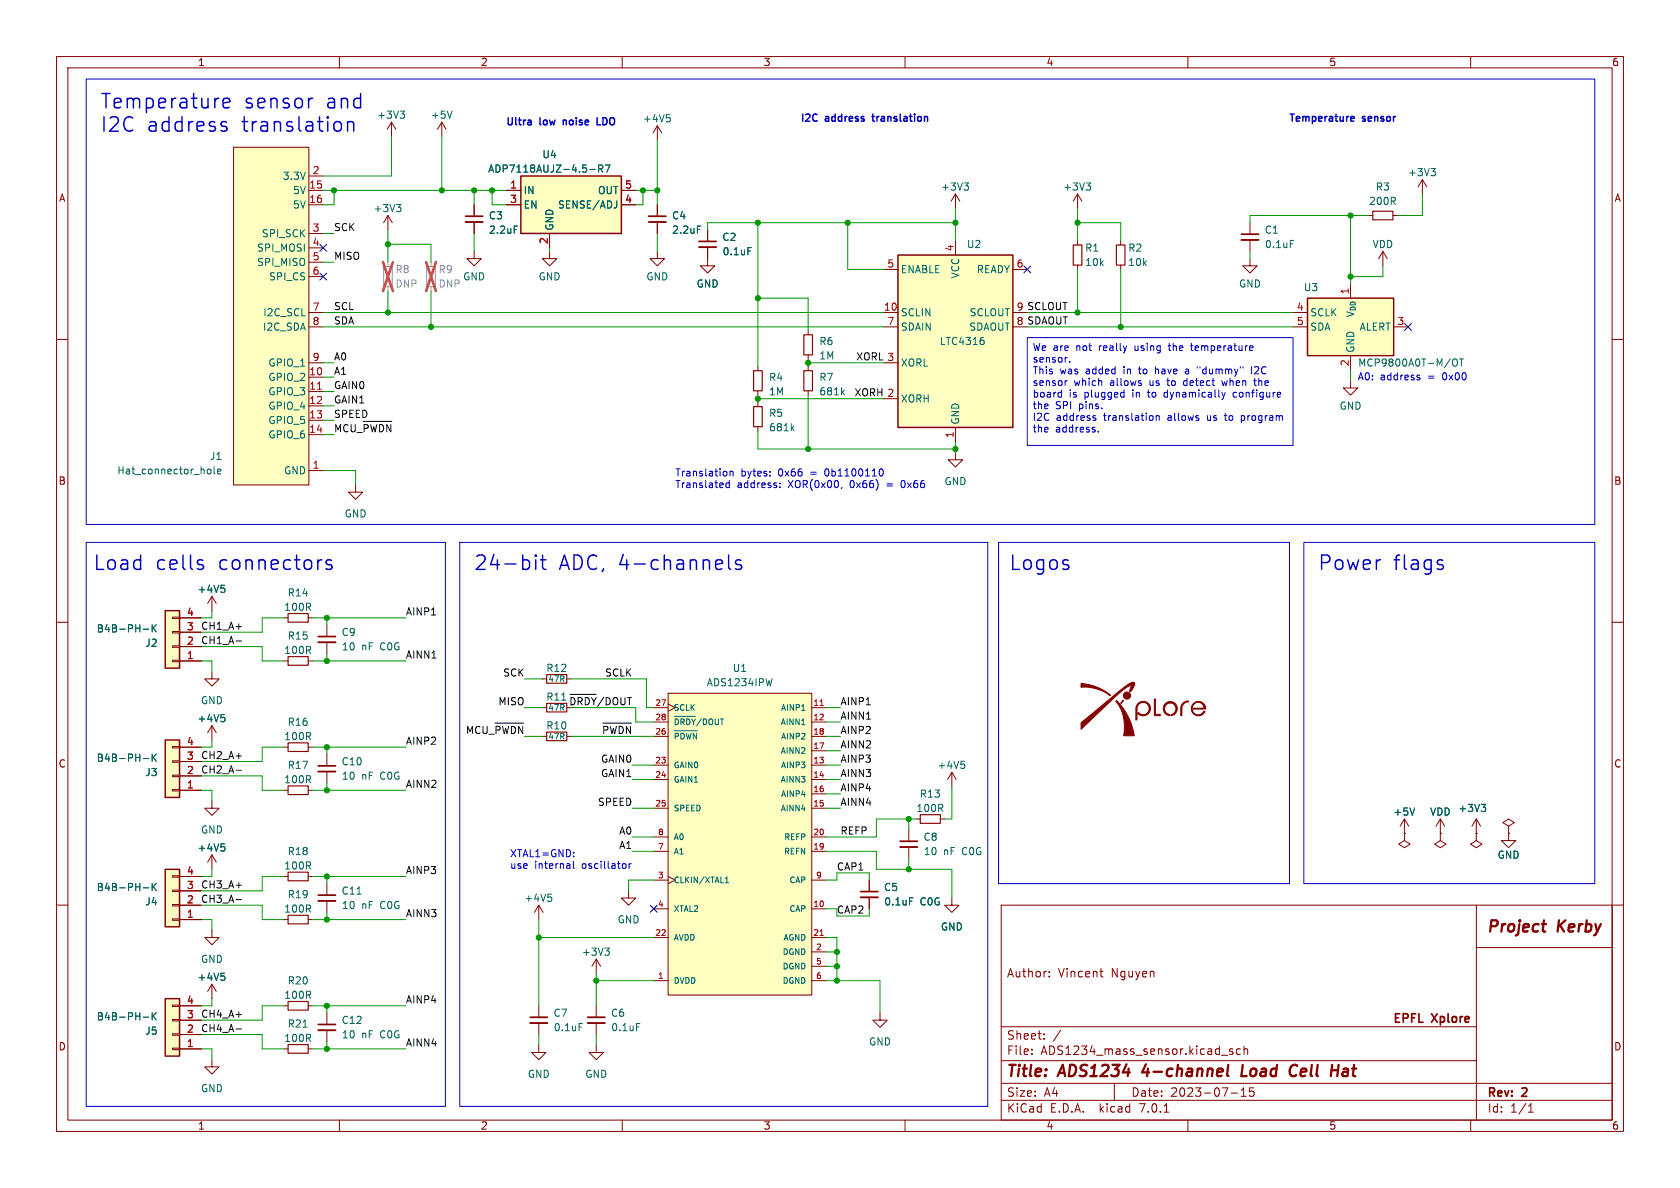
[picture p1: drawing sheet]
<svg xmlns="http://www.w3.org/2000/svg" width="297mm" height="210mm" viewBox="0 0 297 210" stroke-linecap="round" stroke-linejoin="round" font-family="sans-serif">
<defs><g id="words">
<g font-size="3.5" fill="#0000c2">
<text x="17.8" y="19.4">Temperature</text>
<text x="17.8" y="23.5">I2C</text>
<text x="26" y="23.5">address</text>
<text x="42.8" y="23.5">translation</text>
<text x="43.2" y="19.4">sensor</text>
<text x="57.7" y="19.4">and</text>
<text x="16.5" y="101">Load</text>
<text x="27.5" y="101">cells</text>
<text x="38.7" y="101">connectors</text>
<text x="83.8" y="101">24-bit</text>
<text x="98.8" y="101">ADC, 4-channels</text>
<text x="178.4" y="101">Logos</text>
<text x="233" y="101">Power</text>
<text x="246.4" y="101">flags</text>
</g>
<g font-size="2.8" fill="#840000">
<text x="262.7" y="165.3">Project</text>
<text x="275.2" y="165.3">Kerby</text>
<text x="178" y="190.8">Title:</text>
<text x="187.4" y="190.8">ADS1234</text>
<text x="202.7" y="190.8">4-channel</text>
<text x="220.8" y="190.8">Load</text>
<text x="229.9" y="190.8">Cell</text>
<text x="237.8" y="190.8">Hat</text>
</g>
<g font-size="2.1" fill="#840000">
<text x="178" y="172.9">Author:</text>
<text x="187.1" y="172.9">Vincent</text>
<text x="196.4" y="172.9">Nguyen</text>
<text x="178" y="183.9">Sheet:</text>
<text x="186.2" y="183.9">/</text>
<text x="245.9" y="181.1">EPFL</text>
<text x="252.9" y="181.1">Xplore</text>
<text x="178" y="186.6">File:</text>
<text x="184" y="186.6">ADS1234_mass_sensor.kicad_sch</text>
<text x="178" y="196.8">KiCad</text>
<text x="178" y="194">Size:</text>
<text x="184.6" y="194">A4</text>
<text x="185.7" y="196.8">E.D.A.</text>
<text x="194.4" y="196.8">kicad</text>
<text x="200" y="194">Date:</text>
<text x="201.5" y="196.8">7.0.1</text>
<text x="206.9" y="194">2023-07-15</text>
<text x="263" y="194.2">Rev:</text>
<text x="263" y="196.8">Id:</text>
<text x="267" y="196.8">1/1</text>
<text x="269.2" y="194.2">2</text>
</g>
<g font-size="1.8" fill="#840000">
<text x="35" y="11.8">1</text>
<text x="85" y="11.8">2</text>
<text x="135" y="11.8">3</text>
<text x="185" y="11.8">4</text>
<text x="235" y="11.8">5</text>
<text x="285" y="11.8">6</text>
<text x="10.4" y="35.8">A</text>
<text x="285.4" y="35.8">A</text>
<text x="10.3" y="85.8">B</text>
<text x="285.3" y="85.8">B</text>
<text x="10.3" y="135.8">C</text>
<text x="285.3" y="135.8">C</text>
<text x="10.3" y="185.8">D</text>
<text x="285.3" y="185.8">D</text>
<text x="35" y="199.8">1</text>
<text x="85" y="199.8">2</text>
<text x="135" y="199.8">3</text>
<text x="185" y="199.8">4</text>
<text x="235" y="199.8">5</text>
<text x="285" y="199.8">6</text>
</g>
<g font-size="1.8" fill="#006464">
<text x="66.6" y="21.1">+3V3</text>
<text x="76.1" y="21.1">+5V</text>
<text x="113.6" y="21.8">+4V5</text>
<text x="95.8" y="28.1">U4</text>
<text x="49.9" y="31.9">3.3V</text>
<text x="51.7" y="34.5">5V</text>
<text x="86.2" y="30.7">ADP7118AUJZ-4.5-R7</text>
<text x="92.6" y="34.5">IN</text>
<text x="105.6" y="34.5">OUT</text>
<text x="166.3" y="33.8">+3V3</text>
<text x="187.9" y="33.8">+3V3</text>
<text x="243.2" y="33.8">R3</text>
<text x="248.9" y="31.3">+3V3</text>
<text x="51.7" y="37">5V</text>
<text x="66" y="37.7">+3V3</text>
<text x="86.4" y="38.9">C3</text>
<text x="86.4" y="41.5">2.2uF</text>
<text x="92.6" y="37">EN</text>
<text x="98" y="40.8" transform="rotate(-90 98 40.8)">GND</text>
<text x="98.5" y="37">SENSE/ADJ</text>
<text x="118.8" y="38.9">C4</text>
<text x="118.8" y="41.5">2.2uF</text>
<text x="223.5" y="41.5">C1</text>
<text x="242" y="36.4">200R</text>
<text x="45.3" y="44.6">SPI_MOSI</text>
<text x="45.3" y="47.2">SPI_MISO</text>
<text x="46.2" y="42.1">SPI_SCK</text>
<text x="127.6" y="42.7">C2</text>
<text x="127.7" y="45.3">0.1uF</text>
<text x="170.9" y="44">U2</text>
<text x="191.8" y="44.6">R1</text>
<text x="191.8" y="47.2">10k</text>
<text x="199.4" y="44.6">R2</text>
<text x="199.4" y="47.2">10k</text>
<text x="223.6" y="44">0.1uF</text>
<text x="242.6" y="44">VDD</text>
<text x="47.4" y="49.7">SPI_CS</text>
<text x="81.8" y="49.7">GND</text>
<text x="95.2" y="49.7">GND</text>
<text x="114.2" y="49.7">GND</text>
<text x="123.1" y="51">GND</text>
<text x="159.3" y="48.5">ENABLE</text>
<text x="169.7" y="49.3" transform="rotate(-90 169.7 49.3)">VCC</text>
<text x="172.6" y="48.5">READY</text>
<text x="219" y="51">GND</text>
<text x="230.4" y="51.6">U3</text>
<text x="46.4" y="58.6">I2C_SDA</text>
<text x="46.4" y="56.1">I2C_SCL</text>
<text x="159.3" y="56.1">SCLIN</text>
<text x="159.3" y="58.6">SDAIN</text>
<text x="171.2" y="58.6">SDAOUT</text>
<text x="171.3" y="56.1">SCLOUT</text>
<text x="231.6" y="56.1">SCLK</text>
<text x="231.6" y="58.6">SDA</text>
<text x="239.6" y="56.3" transform="rotate(-90 239.6 56.3)">V_{DD}</text>
<text x="240.2" y="58.6">ALERT</text>
<text x="47.3" y="65">GPIO_1</text>
<text x="144.8" y="61.2">R6</text>
<text x="144.8" y="63.7">1M</text>
<text x="159.3" y="65">XORL</text>
<text x="166.1" y="61.2">LTC4316</text>
<text x="239.6" y="62.4" transform="rotate(-90 239.6 62.4)">GND</text>
<text x="240" y="65">MCP9800A0T-M/OT</text>
<text x="47.3" y="67.5">GPIO_2</text>
<text x="47.3" y="70">GPIO_3</text>
<text x="135.9" y="67.5">R4</text>
<text x="135.9" y="70">1M</text>
<text x="144.8" y="67.5">R7</text>
<text x="144.8" y="70">681k</text>
<text x="159.3" y="71.3">XORH</text>
<text x="47.3" y="72.6">GPIO_4</text>
<text x="47.3" y="75.1">GPIO_5</text>
<text x="47.3" y="77.7">GPIO_6</text>
<text x="135.9" y="73.9">R5</text>
<text x="135.9" y="76.4">681k</text>
<text x="169.7" y="75.1" transform="rotate(-90 169.7 75.1)">GND</text>
<text x="236.8" y="72.6">GND</text>
<text x="37.1" y="81.5">J1</text>
<text x="20.7" y="84">Hat_connector_hole</text>
<text x="50.1" y="84">GND</text>
<text x="166.9" y="85.9">GND</text>
<text x="60.9" y="91.6">GND</text>
<text x="34.9" y="105">+4V5</text>
<text x="50.8" y="105.6">R14</text>
<text x="17" y="112">B4B-PH-K</text>
<text x="50.2" y="108.1">100R</text>
<text x="50.8" y="113.2">R15</text>
<text x="60.3" y="112.6">C9</text>
<text x="25.6" y="114.5">J2</text>
<text x="50.2" y="115.8">100R</text>
<text x="60.4" y="115.1">10</text>
<text x="63.9" y="115.1">nF</text>
<text x="67.2" y="115.1">C0G</text>
<text x="96.5" y="118.9">R12</text>
<text x="129.5" y="118.9">U1</text>
<text x="35.5" y="124.7">GND</text>
<text x="96.5" y="124">R11</text>
<text x="124.9" y="121.5">ADS1234IPW</text>
<text x="34.9" y="127.8">+4V5</text>
<text x="50.2" y="131">100R</text>
<text x="50.8" y="128.5">R16</text>
<text x="96.5" y="129.1">R10</text>
<text x="17" y="134.8">B4B-PH-K</text>
<text x="25.6" y="137.4">J3</text>
<text x="50.8" y="136.1">R17</text>
<text x="60.3" y="135.4">C10</text>
<text x="60.4" y="138">10</text>
<text x="63.9" y="138">nF</text>
<text x="67.2" y="138">C0G</text>
<text x="165.7" y="136.1">+4V5</text>
<text x="50.2" y="138.6">100R</text>
<text x="162" y="143.7">100R</text>
<text x="162.6" y="141.2">R13</text>
<text x="257.7" y="143.7">+3V3</text>
<text x="35.5" y="147.5">GND</text>
<text x="163.2" y="148.8">C8</text>
<text x="246.3" y="144.3">+5V</text>
<text x="252.8" y="144.3">VDD</text>
<text x="34.9" y="150.7">+4V5</text>
<text x="50.2" y="153.9">100R</text>
<text x="50.8" y="151.3">R18</text>
<text x="163.2" y="151.3">10</text>
<text x="166.8" y="151.3">nF</text>
<text x="170.1" y="151.3">C0G</text>
<text x="264.7" y="152">GND</text>
<text x="17" y="157.7">B4B-PH-K</text>
<text x="25.6" y="160.2">J4</text>
<text x="50.2" y="161.5">100R</text>
<text x="50.8" y="158.9">R19</text>
<text x="60.3" y="158.3">C11</text>
<text x="60.4" y="160.9">10</text>
<text x="63.9" y="160.9">nF</text>
<text x="67.2" y="160.9">C0G</text>
<text x="92.6" y="159.6">+4V5</text>
<text x="156.2" y="157.7">C5</text>
<text x="156.3" y="160.2">0.1uF</text>
<text x="162.6" y="160.2">C0G</text>
<text x="109.1" y="163.4">GND</text>
<text x="166.3" y="164.7">GND</text>
<text x="34.9" y="173.5">+4V5</text>
<text x="35.5" y="170.4">GND</text>
<text x="102.8" y="169.1">+3V3</text>
<text x="50.2" y="176.7">100R</text>
<text x="50.8" y="174.2">R20</text>
<text x="97.8" y="179.9">C7</text>
<text x="108" y="179.9">C6</text>
<text x="17" y="180.5">B4B-PH-K</text>
<text x="25.6" y="183.1">J5</text>
<text x="50.2" y="184.3">100R</text>
<text x="50.8" y="181.8">R21</text>
<text x="60.3" y="181.2">C12</text>
<text x="60.4" y="183.7">10</text>
<text x="63.9" y="183.7">nF</text>
<text x="67.2" y="183.7">C0G</text>
<text x="97.8" y="182.4">0.1uF</text>
<text x="108" y="182.4">0.1uF</text>
<text x="153.6" y="185">GND</text>
<text x="93.3" y="190.7">GND</text>
<text x="103.4" y="190.7">GND</text>
<text x="35.5" y="193.2">GND</text>
</g>
<g font-size="1.8" fill="#0000c2">
<text x="89.5" y="22.2">Ultra</text>
<text x="95.5" y="22.2">low</text>
<text x="100" y="22.2">noise</text>
<text x="106.4" y="22.2">LDO</text>
<text x="141.6" y="21.6">I2C</text>
<text x="146" y="21.6">address</text>
<text x="154.8" y="21.6">translation</text>
<text x="228" y="21.6">Temperature</text>
<text x="241" y="21.6">sensor</text>
<text x="182.6" y="62.3">We are</text>
<text x="182.6" y="64.4">sensor.</text>
<text x="190.3" y="62.3">not</text>
<text x="194.4" y="62.3">really</text>
<text x="200.9" y="62.3">using</text>
<text x="207" y="62.3">the</text>
<text x="211.1" y="62.3">temperature</text>
<text x="182.6" y="66.4">This</text>
<text x="182.6" y="68.5">sensor</text>
<text x="182.6" y="70.5">board</text>
<text x="187.4" y="66.4">was</text>
<text x="189" y="70.5">is</text>
<text x="189.9" y="68.5">which</text>
<text x="191.8" y="70.5">plugged</text>
<text x="192" y="66.4">added</text>
<text x="196.3" y="68.5">allows</text>
<text x="198.8" y="66.4">in</text>
<text x="200.4" y="70.5">in</text>
<text x="201.6" y="66.4">to</text>
<text x="203.2" y="70.5">to</text>
<text x="203.4" y="68.5">us</text>
<text x="204.6" y="66.4">have</text>
<text x="206.2" y="70.5">dynamically</text>
<text x="206.7" y="68.5">to</text>
<text x="209.6" y="68.5">detect</text>
<text x="210.1" y="66.4">a</text>
<text x="212.3" y="66.4">&quot;dummy&quot;</text>
<text x="216.6" y="68.5">when</text>
<text x="218.5" y="70.5">configure</text>
<text x="222" y="66.4">I2C</text>
<text x="222.4" y="68.5">the</text>
<text x="240" y="67.3">A0:</text>
<text x="244" y="67.3">address</text>
<text x="252.5" y="67.3">=</text>
<text x="255.2" y="67.3">0x00</text>
<text x="182.6" y="72.6">the</text>
<text x="182.6" y="74.6">I2C</text>
<text x="182.6" y="76.7">the</text>
<text x="186.6" y="72.6">SPI</text>
<text x="186.6" y="76.7">address.</text>
<text x="186.7" y="74.6">address</text>
<text x="190.8" y="72.6">pins.</text>
<text x="195.2" y="74.6">translation</text>
<text x="206.6" y="74.6">allows</text>
<text x="213.7" y="74.6">us</text>
<text x="216.9" y="74.6">to</text>
<text x="219.9" y="74.6">program</text>
<text x="119.4" y="84.3">Translation</text>
<text x="119.4" y="86.4">Translated</text>
<text x="130.3" y="86.4">address:</text>
<text x="131" y="84.3">bytes:</text>
<text x="137.7" y="84.3">0x66</text>
<text x="139.4" y="86.4">XOR(0x00,</text>
<text x="143.4" y="84.3">=</text>
<text x="146.1" y="84.3">0b1100110</text>
<text x="150.4" y="86.4">0x66)</text>
<text x="157" y="86.4">=</text>
<text x="159.7" y="86.4">0x66</text>
<text x="90.2" y="151.6">XTAL1=GND:</text>
<text x="90.2" y="153.7">use</text>
<text x="94.5" y="153.7">internal</text>
<text x="102.9" y="153.7">oscillator</text>
</g>
<g font-size="1.8" fill="#a90000">
<text x="54.6" y="33.4">15</text>
<text x="54.6" y="35.9">16</text>
<text x="55.2" y="30.9">2</text>
<text x="90.1" y="33.4">1</text>
<text x="90.1" y="35.9">3</text>
<text x="110.5" y="33.4">5</text>
<text x="110.5" y="35.9">4</text>
<text x="55.2" y="41">3</text>
<text x="55.2" y="43.6">4</text>
<text x="55.2" y="46.1">5</text>
<text x="96.9" y="43.2" transform="rotate(-90 96.9 43.2)">2</text>
<text x="156.8" y="47.4">5</text>
<text x="168.7" y="44.5" transform="rotate(-90 168.7 44.5)">4</text>
<text x="179.7" y="47.4">6</text>
<text x="55.2" y="48.6">6</text>
<text x="238.5" y="52.1" transform="rotate(-90 238.5 52.1)">1</text>
<text x="55.2" y="55">7</text>
<text x="55.2" y="57.5">8</text>
<text x="156.2" y="55">10</text>
<text x="156.8" y="57.5">7</text>
<text x="229.2" y="55">4</text>
<text x="229.2" y="57.5">5</text>
<text x="247" y="57.5">3</text>
<text x="55.2" y="63.9">9</text>
<text x="238.5" y="64.8" transform="rotate(-90 238.5 64.8)">2</text>
<text x="54.6" y="66.4">10</text>
<text x="54.6" y="69">11</text>
<text x="54.6" y="71.5">12</text>
<text x="54.6" y="74">13</text>
<text x="54.6" y="76.6">14</text>
<text x="168.7" y="77.5" transform="rotate(-90 168.7 77.5)">1</text>
<text x="55.2" y="82.9">1</text>
<text x="33" y="111.5">3</text>
<text x="33" y="109">4</text>
<text x="33" y="116.6">1</text>
<text x="33" y="114">2</text>
<text x="33" y="131.8">4</text>
<text x="33" y="136.9">2</text>
<text x="33" y="134.4">3</text>
<text x="33" y="139.4">1</text>
<text x="33" y="154.7">4</text>
<text x="33" y="159.8">2</text>
<text x="33" y="157.2">3</text>
<text x="33" y="162.3">1</text>
<text x="33" y="177.5">4</text>
<text x="33" y="185.2">1</text>
<text x="33" y="182.6">2</text>
<text x="33" y="180.1">3</text>
</g>
<g font-size="1.8" fill="#0f0f0f">
<text x="59.1" y="40.9">SCK</text>
<text x="59.1" y="46">MISO</text>
<text x="59.1" y="54.9">SCL</text>
<text x="59.1" y="57.4">SDA</text>
<text x="179.7" y="57.5">8 SDAOUT</text>
<text x="179.7" y="55">9 SCLOUT</text>
<text x="59.1" y="63.8">A0</text>
<text x="151.2" y="63.8">XORL 3</text>
<text x="59.1" y="68.9">GAIN0</text>
<text x="59.1" y="71.4">GAIN1</text>
<text x="59.1" y="66.3">A1</text>
<text x="150.9" y="70.1">XORH 2</text>
<text x="59.1" y="76.5">MCU_~{PWDN}</text>
<text x="59.1" y="73.9">SPEED</text>
<text x="35.6" y="114">CH1_A-</text>
<text x="35.6" y="111.4">CH1_A+</text>
<text x="71.8" y="108.9">AINP1</text>
<text x="71.8" y="116.5">AINN1</text>
<text x="88.8" y="119.7">SCK</text>
<text x="106.9" y="119.7">SCLK</text>
<text x="88" y="124.7">MISO</text>
<text x="100.5" y="124.7">~{DRDY}/DOUT</text>
<text x="148.6" y="124.7">AINP1</text>
<text x="71.8" y="131.7">AINP2</text>
<text x="82.2" y="129.8">MCU_~{PWDN}</text>
<text x="106.3" y="129.8">~{PWDN}</text>
<text x="148.6" y="127.3">AINN1</text>
<text x="148.6" y="129.8">AINP2</text>
<text x="35.6" y="136.8">CH2_A-</text>
<text x="35.6" y="134.3">CH2_A+</text>
<text x="106.1" y="134.9">GAIN0</text>
<text x="106.1" y="137.4">GAIN1</text>
<text x="148.6" y="134.9">AINP3</text>
<text x="148.6" y="137.4">AINN3</text>
<text x="148.6" y="132.4">AINN2</text>
<text x="71.8" y="139.4">AINN2</text>
<text x="105.6" y="142.5">SPEED</text>
<text x="148.6" y="140">AINP4</text>
<text x="148.6" y="142.5">AINN4</text>
<text x="109.3" y="147.6">A0</text>
<text x="148.6" y="147.6">REFP</text>
<text x="71.8" y="154.6">AINP3</text>
<text x="109.3" y="150.1">A1</text>
<text x="148" y="154">CAP1</text>
<text x="35.6" y="159.7">CH3_A-</text>
<text x="35.6" y="157.1">CH3_A+</text>
<text x="71.8" y="162.2">AINN3</text>
<text x="35.6" y="180">CH4_A+</text>
<text x="71.8" y="177.5">AINP4</text>
<text x="35.6" y="182.5">CH4_A-</text>
<text x="71.8" y="185.1">AINN4</text>
</g>
<g font-size="1.8" fill="#989898">
<text x="69.9" y="48.5">R8</text>
<text x="69.9" y="51">DNP</text>
<text x="77.5" y="48.5">R9</text>
<text x="77.5" y="51">DNP</text>
</g>
<text font-size="1.8" fill="#009600" x="148" y="161.6">CAP2</text>
<g font-size="1.4" fill="#006464">
<text x="96.9" y="125.8">47R</text>
<text x="96.9" y="120.7">47R</text>
<text x="119.1" y="125.8">SCLK</text>
<text x="137.9" y="125.8">AINP1</text>
<text x="96.9" y="130.9">47R</text>
<text x="119.1" y="131.4">~{PDWN}</text>
<text x="119.1" y="128.8">~{DRDY}/DOUT</text>
<text x="137.9" y="128.3">AINN1</text>
<text x="137.9" y="130.9">AINP2</text>
<text x="119.1" y="136">GAIN0</text>
<text x="137.9" y="133.4">AINN2</text>
<text x="137.9" y="136">AINP3</text>
<text x="119.1" y="138.5">GAIN1</text>
<text x="119.1" y="143.6">SPEED</text>
<text x="137.9" y="138.5">AINN3</text>
<text x="137.9" y="143.6">AINN4</text>
<text x="137.9" y="141">AINP4</text>
<text x="119.1" y="148.7">A0</text>
<text x="138.5" y="148.7">REFP</text>
<text x="119.1" y="151.2">A1</text>
<text x="138.4" y="151.2">REFN</text>
<text x="119.1" y="156.3">CLKIN/XTAL1</text>
<text x="119.1" y="161.4">XTAL2</text>
<text x="139.4" y="161.4">CAP</text>
<text x="139.4" y="156.3">CAP</text>
<text x="119.1" y="166.4">AVDD</text>
<text x="138.3" y="166.4">AGND</text>
<text x="138.2" y="169">DGND</text>
<text x="138.2" y="171.5">DGND</text>
<text x="119.1" y="174.1">DVDD</text>
<text x="138.2" y="174.1">DGND</text>
</g>
<g font-size="1.4" fill="#a90000">
<text x="115.8" y="124.8">27</text>
<text x="143.7" y="124.8">11</text>
<text x="115.8" y="129.9">26</text>
<text x="115.8" y="127.4">28</text>
<text x="143.7" y="127.4">12</text>
<text x="143.7" y="129.9">18</text>
<text x="115.8" y="135">23</text>
<text x="115.8" y="137.5">24</text>
<text x="143.7" y="135">13</text>
<text x="143.7" y="137.5">14</text>
<text x="143.7" y="132.5">17</text>
<text x="115.8" y="142.6">25</text>
<text x="143.7" y="142.6">15</text>
<text x="143.7" y="140.1">16</text>
<text x="116.3" y="147.7">8</text>
<text x="143.7" y="147.7">20</text>
<text x="116.3" y="155.3">3</text>
<text x="116.3" y="150.2">7</text>
<text x="143.7" y="150.2">19</text>
<text x="144.2" y="155.3">9</text>
<text x="116.3" y="160.4">4</text>
<text x="143.7" y="160.4">10</text>
<text x="115.8" y="165.5">22</text>
<text x="143.7" y="165.5">21</text>
<text x="116.3" y="173.1">1</text>
<text x="144.2" y="168">2</text>
<text x="144.2" y="170.6">5</text>
<text x="144.2" y="173.1">6</text>
</g>
</g></defs>
<g fill="none" stroke="#840000" stroke-width=".18">
<path d="M10 10h277v190h-277zM12 12h273v186h-273zM60 10v2M110 10v2M160 10v2M210 10v2M260 10v2M41.3 26h13.3v59.7h-13.3zM54.6 33.7h2.5M54.6 36.2h2.5M54.6 31.1h2.5M68.6 38.1l-.8 1.3"/>
<path d="M68.6 38.1v2.5M68.6 38.1l.7 1.3M69.2 21.6l-.7 1.3M69.2 21.6v2.5M69.2 21.6l.8 1.3M78.1 21.6l-.8 1.3M78.1 21.6v2.5M78.1 21.6l.8 1.3M83.8 36.2v2M83.8 39.2v2.1M89.5 33.7h2.6M89.5 36.2h2.6"/>
<path d="M109.9 33.7h2.5M109.9 36.2h2.5M116.2 22.2v2.6M116.2 36.2v2M116.2 39.2v2.1M116.2 22.2l-.8 1.3M116.2 22.2l.8 1.3M168.9 34.3v2.5M168.9 34.3l.8 1.3M168.9 34.3l-.8 1.3M190.5 34.3l-.8 1.3M190.5 34.3v2.5"/>
<path d="M190.5 34.3l.8 1.3M221 39.4v2M241.9 38.1h.8M246.3 38.1h.7M251.5 31.8l-.8 1.2M251.5 31.8v2.5M251.5 31.8l.7 1.2M10 60h2M54.6 57.8h2.5M54.6 55.2h2.5M54.6 41.3h2.5M54.6 43.8h2.5"/>
<path d="M54.6 46.4h2.5M54.6 48.9h2.5M83.8 44.5v1.2h-1.3l1.3 1.3 1.3-1.3h-1.3M97.2 44.5v1.2h-1.3l1.3 1.3 1.2-1.3h-1.2M97.2 41.3v2.5M116.2 44.5v1.2h-1.3l1.3 1.3 1.3-1.3h-1.3M125.1 43.7v3.3h-1.3l1.3 1.3 1.3-1.3h-1.3M125.1 40.6v2.1M142.9 58.4v.8M156.2 57.8h2.5M156.2 55.2h2.5M156.2 47.6h2.5"/>
<path d="M168.9 42.5v2.6M179.1 57.8h2.5M179.1 55.2h2.5M179.1 47.6h2.5M190.5 42.5v.8M190.5 46.9v.7M198.1 42.5v.8M198.1 46.9v.7M221 45.7v1.3h-1.3l1.3 1.3 1.2-1.3h-1.2M221 42.4v2.1M228.6 57.8h2.5M228.6 55.2h2.5"/>
<path d="M244.5 44.5l-.8 1.2M244.5 44.5v2.5M244.5 44.5l.7 1.2M246.4 57.8h2.5M285 60h2M54.6 66.7h2.5M54.6 69.2h2.5M54.6 71.8h2.5M54.6 74.3h2.5M54.6 76.8h2.5M54.6 64.1h2.5M134 64.8v.7"/>
<path d="M134 69.1v.8M134 71.1v.8M134 75.4v.8M142.9 62.7v.8M142.9 64.8v.7M142.9 69.1v.8M156.2 64.1h2.5M156.2 70.5h2.5M168.9 75.6v2.5M238.8 67.3v1.3h1.2l-1.2 1.3-1.3-1.3h1.3M238.8 62.9v2.5M54.6 83.2h2.5"/>
<path d="M62.9 85.7v1.3h1.2l-1.2 1.3-1.3-1.3h1.3M168.9 80v1.3h1.3l-1.3 1.3-1.3-1.3h1.3M10 110h2M30.5 109.1h1.2v.2h-1.2zM30.5 111.6h1.2v.3h-1.2zM30.5 114.2h1.2v.2h-1.2zM30.5 116.7h1.2v.3h-1.2zM31.7 116.8h3.9M31.7 114.3h3.9M31.7 111.8h3.9M31.7 109.2h3.9M37.5 118.7v1.3h-1.3l1.3 1.3 1.2-1.3h-1.2"/>
<path d="M37.5 105.4v2.6M37.5 105.4l-.8 1.3M37.5 105.4l.7 1.3M50.2 116.8h.7M50.2 109.2h.7M54.5 116.8h.7M54.5 109.2h.7M57.8 110.5v2M57.8 113.5v2.1M285 110h2M30.5 132h1.2v.2h-1.2zM30.5 134.5h1.2v.2h-1.2z"/>
<path d="M30.5 137h1.2v.3h-1.2zM30.5 139.6h1.2v.2h-1.2zM31.7 132.1h3.9M31.7 139.7h3.9M31.7 137.2h3.9M31.7 134.6h3.9M37.5 128.3v2.5M37.5 128.3l-.8 1.2M37.5 128.3l.7 1.2M50.2 132.1h.7M50.2 139.7h.7M54.5 132.1h.7"/>
<path d="M54.5 139.7h.7M57.8 133.4v2M57.8 136.4v2M95.9 130.2h.7M95.9 125.1h.7M95.9 120h.7M100.2 130.2h.8M100.2 120h.8M115.6 130.2h2.5M115.6 125.1h2.5M115.6 127.6h2.5M115.6 135.3h2.5"/>
<path d="M115.6 137.8h2.5M118.1 122.6h25.4v53.3h-25.4zM118.1 124.5l1.3 .6-1.3 .6M143.5 130.2h2.5M143.5 125.1h2.5M143.5 127.6h2.5M143.5 135.3h2.5M143.5 137.8h2.5M143.5 132.7h2.5M168.3 136.5v2.6M168.3 136.5l-.8 1.3M168.3 136.5l.7 1.3"/>
<path d="M10 160h2M30.5 154.8h1.2v.3h-1.2zM30.5 157.4h1.2v.2h-1.2zM30.5 159.9h1.2v.2h-1.2zM31.7 157.5h3.9M31.7 154.9h3.9M37.5 141.6v1.3h-1.3l1.3 1.2 1.2-1.2h-1.2M37.5 151.1v2.6M37.5 151.1l-.8 1.3M37.5 151.1l.7 1.3M50.2 154.9h.7M54.5 154.9h.7"/>
<path d="M57.8 156.2v2M57.8 159.3v2M111.1 157.5v1.3h1.3l-1.3 1.2-1.2-1.2h1.2M115.6 142.9h2.5M115.6 150.5h2.5M115.6 148h2.5M115.6 155.6h2.5M118.1 154.9l1.3 .7-1.3 .6M143.5 142.9h2.5M143.5 140.3h2.5M143.5 150.5h2.5M143.5 148h2.5"/>
<path d="M143.5 155.6h2.5M153.7 155.6v2M153.7 158.6v2.1M160.7 146.7v2M160.7 149.7v2.1M161.9 144.8h.8M166.2 144.8h.8M168.3 158.8v1.2h1.2l-1.2 1.3-1.3-1.3h1.3M248.3 147.3v1.3l1 .6-1 .7-1-.7 1-.6M248.3 147.3h.1M248.3 144.8l-.8 1.3M248.3 144.8v2.5"/>
<path d="M248.3 144.8l.7 1.3M254.6 147.3v1.3l1.1 .6-1.1 .7-1-.7 1-.6M254.6 147.3h.1M254.6 144.8l-.7 1.3M254.6 144.8v2.5M254.6 144.8l.8 1.3M261 147.3v1.3l1 .6-1 .7-1-.7 1-.6M261 147.3h.1M261 144.8v2.5M261 144.8l.7 1.3M261 144.8l-.8 1.3M266.7 147.3v1.3h1.3l-1.3 1.3-1.3-1.3h1.3"/>
<path d="M266.7 146.1l1-.7-1-.6-1 .6 1 .7v1.2M266.7 147.3h.1M285 160h2M30.5 162.4h1.2v.3h-1.2zM30.5 177.7h1.2v.2h-1.2zM31.7 162.6h3.9M31.7 160h3.9M31.7 177.8h3.9M37.5 164.5v1.2h-1.3l1.3 1.3 1.2-1.3h-1.2M37.5 174v2.5M37.5 174l-.8 1.3M37.5 174l.7 1.3"/>
<path d="M50.2 162.6h.7M50.2 177.8h.7M54.5 162.6h.7M54.5 177.8h.7M57.8 179.1v2M95.2 160v2.6M95.2 177.8v2M95.2 160l-.7 1.3M95.2 160l.8 1.3M105.4 169.5l-.8 1.3M105.4 169.5v2.6M105.4 177.8v2"/>
<path d="M105.4 169.5l.8 1.3M115.6 173.4h2.5M115.6 160.7h2.5M115.6 165.7h2.5M143.5 173.4h2.5M143.5 160.7h2.5M143.5 168.3h2.5M143.5 165.7h2.5M143.5 170.8h2.5M155.6 179.1v1.2h1.2l-1.2 1.3-1.3-1.3h1.3M177 160h108v38h-108zM185.5 172.6v.1"/>
<path d="M185.5 171.8v.1M194.4 171.7h.6M194.7 172.6l.3 .1M261 160v38M261 167.5h24M30.5 180.2h1.2v.3h-1.2zM30.5 182.8h1.2v.2h-1.2zM30.5 185.3h1.2v.2h-1.2zM31.7 185.4h3.9M31.7 182.9h3.9M31.7 180.3h3.9M37.5 187.3v1.3h-1.3l1.3 1.3 1.2-1.3h-1.2"/>
<path d="M50.2 185.4h.7M54.5 185.4h.7M57.8 182.1v2.1M60 198v2M95.2 184.8v1.3h1.3l-1.3 1.2-1.2-1.2h1.2M95.2 180.8v2.1M105.4 184.8v1.3h1.3l-1.3 1.2-1.3-1.2h1.3M105.4 180.8v2.1M110 198v2M160 198v2M177 194.5h108M177 191.5h108"/>
<path d="M177 187.5h84M177 181.5h84M182.4 186.3v.1M182.4 185.5v.1M184.6 183.6v.1M184.6 182.8v.1M197 191.5v3M205.8 196.6h.8M210 198v2M215.9 186.5h1.2M217.6 193.2h1.2M217.9 185.5l-.3-.1-.2 .2v.2l.5 .2v.3h-.5"/>
<path d="M219.3 185.5l-.4-.1-.3 .3v.4l.1 .2h.6M219.4 193.8h.9M219.4 192.7l.5-.4v1.5M219.9 185.5l.2-.1 .4 .1 .1 .9M219.9 184.9v1.5M221.6 192.3h-.7v.7l.2-.1h.5l.1 .3-.1 .5-.2 .1-.5-.1M260 198v2M270.2 196.6h.9M270.2 195.5l.4-.4v1.5"/>
</g>
<path d="M272.6 163.3h.7M217.1 188.2l-.2 1.7 .3 .3M219.7 188.2l-.2 2h.9M228.5 188.3l.3-.1 .5 .1M229.1 190l-.6 .2M235.4 189.2h1.1M236.7 188.2l-.3 2" fill="none" stroke="#840000" stroke-width=".4"/>
<g fill="none" stroke="#840000" stroke-width=".2">
<path d="M242.7 37.3h3.6v1.6h-3.6zM142.1 59.2h1.5v3.5h-1.5zM189.7 43.3h1.6v3.6h-1.6zM197.4 43.3h1.5v3.6h-1.5zM133.2 71.9h1.5v3.5h-1.5zM133.2 65.5h1.5v3.6h-1.5zM142.1 65.5h1.5v3.6h-1.5zM50.9 116.1h3.6v1.5h-3.6zM50.9 108.5h3.6v1.5h-3.6zM96.6 119.3h3.6v1.5h-3.6zM50.9 131.3h3.6v1.5h-3.6zM50.9 138.9h3.6v1.6h-3.6z"/>
<path d="M96.6 129.4h3.6v1.5h-3.6zM96.6 124.3h3.6v1.6h-3.6zM50.9 154.2h3.6v1.5h-3.6zM162.7 144h3.5v1.5h-3.5zM50.9 161.8h3.6v1.5h-3.6zM50.9 177h3.6v1.6h-3.6zM50.9 184.7h3.6v1.5h-3.6z"/>
</g>
<g fill="none" stroke="#006464" stroke-width=".18">
<path d="M70.7 19.6h.8l-.4 .5M79.9 19.6l-.4 1.3M70.1 36.1h.8l-.4 .5M70.6 36.6l.3 .3v.3l-.3 .2M71.3 20.1l.2 .3v.3l-.2 .2M90.9 40h.6M104.3 29.9h.9M105.8 29.8h.6l.2-.2-.1-.3-.7-.1v1.2M106.1 29.8l.5 .6M107 29.2h.8l-.5 1.2M109 35.5v.9l-.3 .4M117.8 20.3h.6"/>
<path d="M118.3 20.8l.2 .2v.3l-.2 .2M123.3 40h.6M170.4 32.3h.8l-.4 .5M171 32.8l.2 .3v.3l-.2 .2M192 32.3h.8l-.4 .5M192.6 32.8l.2 .3v.3l-.2 .2M253 29.8h.8l-.5 .5M253.5 30.3l.3 .2v.3l-.3 .3M132.2 43.8h.6M228.1 42.5h.6M140 75.7l.4 .5M140.4 75.3l-.5 .5"/>
<path d="M148.9 69.3l.4 .5M149.3 69l-.5 .4M173.9 60.2l.1 .2-.1 .5M256.9 63.6l.2-.1a.43 .43 0 0 1 .5 .4v.4a.42 .42 0 0 1-.4 .4 .42 .42 0 0 1-.4-.4zM258 63.5h.7M258.4 63.5v1.2M36.9 82.9l.3 .1 .1 .2-.1 .5-.3 .1M37.8 82.5v1.1l.2 .2M38.5 83.3l.6-.1-.1-.2-.4-.1-.1 .2v.6h.5M25.3 111.2h1M26.9 110.4v1.3M27.1 111l.5 .7"/>
<path d="M27.6 110.4l-.7 .8M39.1 103.5h.6M39.5 103.9l.3 .3v.3l-.3 .2M136.5 120l-.3 1.2M25.3 134.1h1M26.9 133.3v1.3M27.1 133.8l.5 .8M27.6 133.3l-.7 .7M39.1 126.3h.6M39.5 126.8l.3 .2v.3l-.3 .3M119.2 129.2h4.1M119.2 126.6h3.7"/>
<path d="M119.9 127.3l-.1-.2h-.4v1M119.9 130v-.3l-.5-.1v1M120.9 129.9l-.1-.2-.4-.1v1M121 127.4l-.1-.3h-.5v1M121.3 129.6l.2 1M121.9 127.3l-.1-.2h-.4v1M122.2 129.6l-.3 1M122.3 127.1l.3 .5 .3-.5M123.1 129.6v1l-.5-1v1M124 127l-.9 1.3M124.9 127.3l-.2-.2h-.3v1M125.3 127.4a.34 .34 0 0 1 .4-.3 .34 .34 0 0 1 .3 .3"/>
<path d="M126.4 127.1v.8M127 127.1v.8M127.4 127.1h.5M127.6 127.1v1M141.7 125.6h.6M141.7 128.1h.6M169.9 134.6h.6M170.3 135.1l.3 .2v.3l-.3 .2M25.3 156.9h1M26.9 156.2v1.2M27.1 156.7l.5 .7M27.6 156.2l-.7 .7"/>
<path d="M39.1 149.2h.6M39.5 149.7l.3 .2v.3l-.3 .2M96.9 158.1h.6M97.3 158.6l.2 .2v.3l-.2 .2M128.2 156h.6M128.2 155.3l.3-.3v1M160.8 158.7h.6M250.1 142.8l-.4 1.3M261.9 142.2h.7l-.4 .5M262.4 142.7l.2 .2v.3l-.2 .3M25.3 179.8h1M26.9 179v1.3"/>
<path d="M27.1 179.6l.5 .7M27.6 179l-.7 .7M39.1 172h.6M39.5 172.5l.3 .3v.3l-.3 .2M106.9 167.6h.8l-.4 .5M107.5 168.1l.2 .2v.3l-.2 .3M102.4 180.9h.6M112.5 180.9h.6"/>
</g>
<g fill="#ffffc2" stroke="#ffffc2" stroke-width=".18">
<path d="M29.2 153.7h2.5v10.1h-2.5z"/>
<path d="M231.1 52.7h15.3v10.2h-15.3z"/>
<path d="M92.1 31.1h17.8v10.2h-17.8z"/>
<path d="M29.2 176.5h2.5v10.2h-2.5z"/>
<path d="M41.3 26h13.3v59.7h-13.3z"/>
<path d="M158.7 45.1h20.4v30.5h-20.4z"/>
<path d="M118.1 122.6h25.4v53.3h-25.4z"/>
<path d="M29.2 130.8h2.5v10.2h-2.5z"/>
<path d="M29.2 108h2.5v10.1h-2.5z"/>
</g>
<path d="M92.1 31.1h17.8v10.2h-17.8zM158.7 45.1h20.4v30.5h-20.4zM231.1 52.7h15.3v10.2h-15.3zM29.2 108h2.5v10.1h-2.5zM29.2 130.8h2.5v10.2h-2.5zM29.2 153.7h2.5v10.1h-2.5zM29.2 176.5h2.5v10.2h-2.5z" fill="none" stroke="#840000" stroke-width=".25"/>
<path d="M82.3 39.2h3M114.7 39.2h3M123.6 43.7h3M219.5 42.4h3M56.3 113.5h3M56.3 136.4h3M56.3 159.3h3M152.1 158.6h3.1M159.1 149.7h3.1M56.3 182.1h3M93.7 180.8h3.1M103.9 180.8h3" fill="none" stroke="#840000" stroke-width=".33"/>
<path d="M82.3 38.2h3M114.7 38.2h3M123.6 42.7h3M219.5 41.4h3M56.3 112.5h3M56.3 135.4h3M56.3 158.2h3M152.1 157.6h3.1M159.1 148.7h3.1M93.7 179.8h3.1M103.9 179.8h3M56.3 181.1h3" fill="none" stroke="#840000" stroke-width=".3"/>
<path d="M67.8 47.1h1.5v3.6h-1.5zM75.4 47.1h1.6v3.6h-1.6z" fill="none" stroke="#a1a1a1" stroke-width=".2"/>
<path d="M68.6 46.4v.7M68.6 50.7v.7M76.2 46.4v.7M76.2 50.7v.7" fill="none" stroke="#a1a1a1" stroke-width=".18"/>
<path d="M67.7 46.4l1.7 5M69.4 46.4l-1.7 5M75.3 46.4l1.8 5M77.1 46.4l-1.8 5" fill="none" stroke="#eb3a3d" stroke-width=".46"/>
<path d="M56.1 68.8h.7M145 124.7h.6M145 165.4h.6" fill="none" stroke="#a90000" stroke-width=".18"/>
<g fill="#840000" stroke="#840000" stroke-width=".18">
<path d="M204.1 123.6h.2v2.7h.8v.2h-1z"/>
<path d="M198.5 123.8h.1l-.4 .6-.1-.1z"/>
<path d="M209.1 124.3l.7-.4h.3v.2a1.32 1.32 0 0 0-1.2 1.7v.7h-.2v-.9a1.67 1.67 0 0 1 .4-1.3z"/>
<path d="M197.4 123.8a11.4 11.4 0 0 1 3.1 6.3h-1.9l.1-.2a7.3 7.3 0 0 0-1.4-5.9z"/>
<path d="M191.1 120.8h.2a9.5 9.5 0 0 1 5 2.1l-.1 .1a7.2 7.2 0 0 0-5.1-1.5z"/>
<path d="M201.2 124.3a1.28 1.28 0 0 1 1.8 0 1.28 1.28 0 0 1 0 1.9 1.28 1.28 0 0 1-1.8 0v-.3l.2 .2a1.07 1.07 0 0 0 1.6-.3 1.07 1.07 0 0 0-.6-1.6 1.07 1.07 0 0 0-1.4 .9v2.2h-.2v-1.7a1.46 1.46 0 0 1 .4-1.3z"/>
<path d="M206 124.4l.8-.4a1.24 1.24 0 0 1 1.3 1.2 1.24 1.24 0 0 1-1.1 1.3v-.2a1.02 1.02 0 0 0 .8-1.5 1.02 1.02 0 0 0-1.7-.1 1.02 1.02 0 0 0 .7 1.6v.2a1.24 1.24 0 0 1-1.1-.8 1.24 1.24 0 0 1 .3-1.3z"/>
<path d="M191.1 127.8l6.9-5.7 1.7-1.3a.56 .56 0 0 1 .9 0l-.6 1.3a.17 .17 0 0 1-.2 .2 .17 .17 0 0 1-.1-.3l.2-.6a.18 .18 0 0 0 0-.2 .18 .18 0 0 0-.2 .1l-2.1 1.4-6.5 6.2z"/>
<path d="M211 124.4a1.26 1.26 0 0 1 1.4-.3 1.26 1.26 0 0 1 .7 1.2l-2.1 .1v-.2h1.9a1.06 1.06 0 0 0-1.5-.9 1.06 1.06 0 0 0-.3 1.7 1.06 1.06 0 0 0 1.7-.2l.2-.1a1.26 1.26 0 0 1-1.8 .6 1.26 1.26 0 0 1-.2-1.9z"/>
<circle cx="199.2" cy="123" r=".63"/>
</g>
<path d="M64.2 74.5h5.1M41.7 113.3h1M41.7 136.2h1M87.5 127.8h5.1M100.8 122.8h4.6M106.6 127.8h5M41.7 159h1M41.7 181.9h1" fill="none" stroke="#0f0f0f" stroke-width=".18"/>
<g fill="none" stroke="#0000c2" stroke-width=".18">
<path d="M15.2 14h266.7v78.7h-266.7zM181.6 59.7h47v19h-47zM187.5 69.4h.1M187.6 68.9v1.3M187.6 70.1l-.1 .1M188.7 67.3l-.3 .1M189.1 63.9v.1M193.6 73.9l.2 .2-.2 .2M194.2 76.3v.1M198.3 69.4h.4M198.7 68.9v1.3M198.7 70.1l-.4 .1"/>
<path d="M201.7 67.8v.3M204.4 73.5v.8M204.4 73.6l.2-.1h.3v.8M210.4 61.1h.5M211.7 64.8v.3M216 69.4l.3 .8M216.3 70.2l-.3 .4M216.6 69.4l-.3 .8M221.1 61.1l.3 .1 .1 .2-.6 .1M221.3 64.8v1.3M221.4 61.9l-.3 .1M221.6 67.3h.5"/>
<path d="M226.2 69.4l.2 .3-.6 .1M226.3 70.1l-.1 .1M250.9 66.7l.1 .2-.1 .3M250.9 66.3l.1 .1M15.2 95.9h63.5v99.7h-63.5zM81.3 95.9h93.3v99.7h-93.3zM128.9 84.9v1.3M128.9 85.4h-.3l-.3 .2 .2 .5h.4M129.1 83.3v.8M129.1 83.4l.1-.1 .3 .1 .1 .7M136.1 84v.1M136.1 83.4v.1"/>
<path d="M137.9 86.1v.1M137.9 85.4v.1M148.8 86.1l-.1 .3M155.4 83.4l.1-.4 .2-.1a.68 .68 0 0 1 .5 .6 .68 .68 0 0 1-.5 .6l-.2-.1-.1-.3M176.5 95.9h51.5v60.3h-51.5zM230.5 95.9h51.4v60.3h-51.4zM101.4 152.2v1.1l.1 .2M110.4 152.7l.3 .2v.4l-.3 .2M111.2 152.7v.8M111.6 152.7l-.4 .2"/>
</g>
<g fill="none" stroke="#0000c2" stroke-width=".25">
<path d="M40.3 17.4l.2 .1 .1 .5-1.2 .2M40.5 18.9l-.2 .2M61.8 21.5l.6 .1 .1 .3v1.3M105.6 20.8v1.3h.6M154.1 20.6h.5M239.2 20.6l.2 .3-.6 .1M239.3 21.4h-.1M94.7 98.1v.3M94.7 99v1.7M94.7 98.1l-.1 .1 .1 .2M94.7 98.1l.1 .1-.1 .2M95.6 99h.9"/>
<path d="M95.9 98.1v2.2l.1 .2 .5 .2M131 99.1l-.6-.1-.4 .3 .1 .4 .9 .2 .1 .3-.1 .3-.3 .2-.7-.2M128.9 100.5l.3 .2"/>
</g>
<g fill="none" stroke="#009600" stroke-width=".18">
<path d="M57.1 33.7h32.4M59.1 33.7v2.5h-2M69.2 24.1v7h-12.1M78.1 24.1v9.6M83.8 33.7v2.5M87 33.7v2.5h2.5M112.4 33.7h3.8M113.7 33.7v2.5h-1.3M116.2 24.8v11.4M134 39.4v25.4M149.9 39.4v8.2h6.3M168.9 39.4h-43.8v1.2"/>
<path d="M168.9 36.8v5.7M190.5 39.4h7.6v3.1M190.5 36.8v5.7M238.8 38.1v12.1M241.9 38.1h-20.9v1.3M251.5 34.3v3.8h-4.5M57.1 41.3h2M57.1 46.4h2M57.1 57.8h99.1M57.1 55.2h99.1M68.6 43.2h7.6v3.2M68.6 40.6v5.8"/>
<path d="M68.6 51.4v3.8M76.2 51.4v6.4M83.8 41.3v3.2M97.2 43.8v.7M116.2 41.3v3.2M134 52.7h8.9v5.7M181.6 57.8h47M181.6 55.2h47M190.5 47.6v7.6M198.1 47.6v10.2M221 44.5v1.2M244.5 47v1.9h-5.7"/>
<path d="M57.1 64.1h2M57.1 69.2h2M57.1 66.7h2M57.1 74.3h2M57.1 71.8h2M57.1 76.8h2M134 69.9v1.2M134 76.2v3.2h34.9M134 70.5h22.2M142.9 63.5v1.3M142.9 69.9v9.5M142.9 64.1h13.3"/>
<path d="M168.9 78.1v1.9M238.8 65.4v1.9M57.1 83.2h5.8v2.5M35.6 116.8h1.9v1.9M35.6 114.3h10.8v2.5h3.8M37.5 108v1.2h-1.9M50.2 109.2h-3.8v2.6h-10.8M55.2 116.8h16.6M55.2 109.2h16.6M57.8 109.2v1.3M57.8 115.6v1.2M35.6 137.2h10.8v2.5h3.8"/>
<path d="M35.6 139.7h1.9v1.9M37.5 130.8v1.3h-1.9M50.2 132.1h-3.8v2.5h-10.8M55.2 132.1h16.6M55.2 139.7h16.6M57.8 132.1v1.3M57.8 138.4v1.3M92.7 125.1h3.2M92.7 130.2h3.2M92.7 120h3.2M101 125.1h11.4v2.5h3.2M101 120h13.3v5.1h1.3"/>
<path d="M101 130.2h14.6M111.8 137.8h3.8M111.8 135.3h3.8M146 125.1h2.6M146 130.2h2.6M146 127.6h2.6M146 137.8h2.6M146 132.7h2.6M146 135.3h2.6M168.3 139.1v5.7h-1.3M37.5 153.7v1.2h-1.9M50.2 154.9h-3.8v2.6h-10.8"/>
<path d="M55.2 154.9h16.6M57.8 154.9v1.3M111.8 148h3.8M111.8 150.5h3.8M111.8 142.9h3.8M115.6 155.6h-4.5v1.9M146 140.3h2.6M146 155.6h2v-1.3h5.7v1.3M146 150.5h8.9v3.2h13.4v5.1M146 142.9h2.6M160.7 144.8v1.9M160.7 151.8v1.9"/>
<path d="M161.9 144.8h-7v3.2h-8.9M35.6 160h10.8v2.6h3.8M35.6 162.6h1.9v1.9M37.5 176.5v1.3h-1.9M50.2 177.8h-3.8v2.5h-10.8M55.2 177.8h16.6M55.2 162.6h16.6M57.8 161.3v1.3M57.8 177.8v1.3M95.2 165.7h20.4M95.2 162.6v15.2M105.4 173.4h10.2"/>
<path d="M105.4 172.1v5.7M146 173.4h9.6v5.7M146 165.7h2v7.7M146 168.3h2M146 170.8h2M146 160.7h2M153.7 160.7v1.2h-5.7M35.6 182.9h10.8v2.5h3.8M35.6 185.4h1.9v1.9M55.2 185.4h16.6M57.8 184.2v1.2M95.2 182.9v1.9"/>
<path d="M105.4 182.9v1.9"/>
</g>
<path d="M56.5 48.3l1.3 1.2M56.5 43.2l1.3 1.2M57.8 48.3l-1.3 1.2M57.8 43.2l-1.3 1.2M181 47l1.2 1.2M182.2 47l-1.2 1.2M248.3 57.2l1.2 1.2M249.5 57.2l-1.2 1.2M115 160l1.2 1.3M116.2 160l-1.2 1.3" fill="none" stroke="#000084" stroke-width=".18"/>
<g fill="#009600" stroke="#009600" stroke-width=".18">
<circle cx="95.2" cy="165.7" r=".46"/>
<circle cx="105.4" cy="173.4" r=".46"/>
<circle cx="160.7" cy="144.8" r=".46"/>
<circle cx="160.7" cy="153.7" r=".46"/>
<circle cx="57.8" cy="154.9" r=".46"/>
<circle cx="57.8" cy="162.6" r=".46"/>
<circle cx="57.8" cy="139.7" r=".46"/>
<circle cx="57.8" cy="177.8" r=".46"/>
<circle cx="57.8" cy="185.4" r=".46"/>
<circle cx="148" cy="173.4" r=".46"/>
<circle cx="148" cy="168.3" r=".46"/>
<circle cx="148" cy="170.8" r=".46"/>
<circle cx="57.8" cy="116.8" r=".46"/>
<circle cx="57.8" cy="109.2" r=".46"/>
<circle cx="57.8" cy="132.1" r=".46"/>
<circle cx="68.6" cy="43.2" r=".46"/>
<circle cx="59.1" cy="33.7" r=".46"/>
<circle cx="76.2" cy="57.8" r=".46"/>
<circle cx="68.6" cy="55.2" r=".46"/>
<circle cx="134" cy="39.4" r=".46"/>
<circle cx="149.9" cy="39.4" r=".46"/>
<circle cx="134" cy="52.7" r=".46"/>
<circle cx="142.9" cy="64.1" r=".46"/>
<circle cx="113.7" cy="33.7" r=".46"/>
<circle cx="116.2" cy="33.7" r=".46"/>
<circle cx="87" cy="33.7" r=".46"/>
<circle cx="83.8" cy="33.7" r=".46"/>
<circle cx="78.1" cy="33.7" r=".46"/>
<circle cx="142.9" cy="79.4" r=".46"/>
<circle cx="134" cy="70.5" r=".46"/>
<circle cx="238.8" cy="48.9" r=".46"/>
<circle cx="238.8" cy="38.1" r=".46"/>
<circle cx="168.9" cy="79.4" r=".46"/>
<circle cx="168.9" cy="39.4" r=".46"/>
<circle cx="190.5" cy="55.2" r=".46"/>
<circle cx="198.1" cy="57.8" r=".46"/>
<circle cx="190.5" cy="39.4" r=".46"/>
</g>
<use href="#words"/>
</svg>
